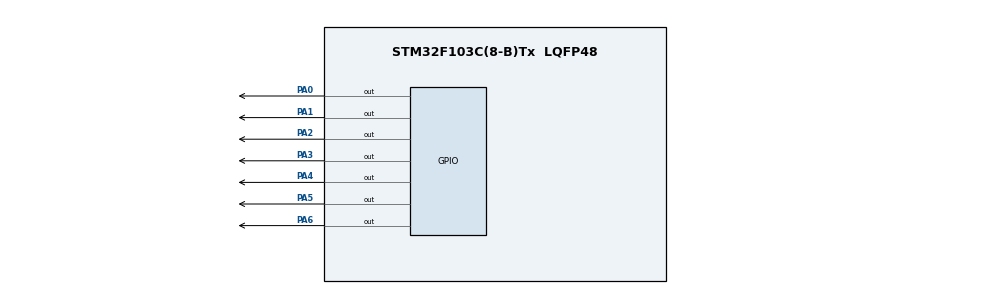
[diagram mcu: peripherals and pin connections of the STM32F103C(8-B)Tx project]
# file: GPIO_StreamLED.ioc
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Mcu.Family=STM32F1
Mcu.Name=STM32F103C(8-B)Tx
Mcu.Package=LQFP48
NVIC.PriorityGroup=NVIC_PRIORITYGROUP_4
PA0-WKUP.Signal=GPIO_Output
PA1.Signal=GPIO_Output
PA13.Mode=Serial_Wire
PA13.Signal=SYS_JTMS-SWDIO
PA14.Mode=Serial_Wire
PA14.Signal=SYS_JTCK-SWCLK
PA2.Signal=GPIO_Output
PA3.Signal=GPIO_Output
PA4.Signal=GPIO_Output
PA5.Signal=GPIO_Output
PA6.Signal=GPIO_Output
PD0-OSC_IN.Mode=HSE-External-Oscillator
PD0-OSC_IN.Signal=RCC_OSC_IN
PD1-OSC_OUT.Mode=HSE-External-Oscillator
PD1-OSC_OUT.Signal=RCC_OSC_OUT
ProjectManager.HeapSize=0x200
ProjectManager.StackSize=0x400
ProjectManager.TargetToolchain=STM32CubeIDE
RCC.AHBFreq_Value=72000000
RCC.APB1CLKDivider=RCC_HCLK_DIV2
RCC.APB1Freq_Value=36000000
RCC.APB1TimFreq_Value=72000000
RCC.APB2Freq_Value=72000000
RCC.APB2TimFreq_Value=72000000
RCC.HCLKFreq_Value=72000000
RCC.PLLMUL=RCC_PLL_MUL9
RCC.PLLSourceVirtual=RCC_PLLSOURCE_HSE
RCC.SYSCLKFreq_VALUE=72000000
RCC.SYSCLKSource=RCC_SYSCLKSOURCE_PLLCLK
RCC.USBFreq_Value=72000000
board=custom

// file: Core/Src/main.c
/* USER CODE BEGIN Header */
/**
  ******************************************************************************
  * @file           : main.c
  * @brief          : Main program body
  ******************************************************************************
  * @attention
  *
  * Copyright (c) 2026 STMicroelectronics.
  * All rights reserved.
  *
  * This software is licensed under terms that can be found in the LICENSE file
  * in the root directory of this software component.
  * If no LICENSE file comes with this software, it is provided AS-IS.
  *
  ******************************************************************************
  */
/* USER CODE END Header */
#include "main.h"

void SystemClock_Config(void);
static void MX_GPIO_Init(void);

int main(void)
{

  /* USER CODE BEGIN 1 */
	uint16_t led_pin[] = {GPIO_PIN_0, GPIO_PIN_1, GPIO_PIN_2, GPIO_PIN_3,
	                      GPIO_PIN_4, GPIO_PIN_5, GPIO_PIN_6};
	uint8_t led_count = sizeof(led_pin) / sizeof(led_pin[0]);
	int8_t led_index = 0;
	uint32_t delay_time = 500; // 每步 500 ms
	int8_t direction = 1; // 1 for forward, -1 for backward
  /* USER CODE END 1 */

  /* MCU Configuration--------------------------------------------------------*/

  /* Reset of all peripherals, Initializes the Flash interface and the Systick. */
  HAL_Init();

  /* Configure the system clock */
  SystemClock_Config();

  /* Initialize all configured peripherals */
  MX_GPIO_Init();

  /* Infinite loop */
  while (1)
  {

    /* USER CODE BEGIN 3 */
	  for (uint8_t i = 0; i < led_count; i++) {
		  HAL_GPIO_WritePin(GPIOA, led_pin[i], GPIO_PIN_RESET);
	  }
	  HAL_GPIO_WritePin(GPIOA, led_pin[led_index], GPIO_PIN_SET);

	  HAL_Delay(delay_time);

	  if (led_index >= led_count - 1) {
		  direction = -1;
	  } else if (led_index <= 0) {
		  direction = 1;
	  }
	  led_index += direction;
  }
  /* USER CODE END 3 */
}

void SystemClock_Config(void)
{
  RCC_OscInitTypeDef RCC_OscInitStruct = {0};
  RCC_ClkInitTypeDef RCC_ClkInitStruct = {0};
  uint32_t sysclk_source = RCC_SYSCLKSOURCE_PLLCLK;

  /** Initializes the RCC Oscillators according to the specified parameters
  * in the RCC_OscInitTypeDef structure.
  */
  RCC_OscInitStruct.OscillatorType = RCC_OSCILLATORTYPE_HSE;
  RCC_OscInitStruct.HSEState = RCC_HSE_ON;
  RCC_OscInitStruct.HSEPredivValue = RCC_HSE_PREDIV_DIV1;
  RCC_OscInitStruct.HSIState = RCC_HSI_ON;
  RCC_OscInitStruct.PLL.PLLState = RCC_PLL_ON;
  RCC_OscInitStruct.PLL.PLLSource = RCC_PLLSOURCE_HSE;
  RCC_OscInitStruct.PLL.PLLMUL = RCC_PLL_MUL9;
  if (HAL_RCC_OscConfig(&RCC_OscInitStruct) != HAL_OK)
  {
    /* HSE 起振失败：退回内部 HSI(8MHz)，保证 GPIO 仍能正常初始化 */
    RCC_OscInitStruct.OscillatorType = RCC_OSCILLATORTYPE_HSI;
    RCC_OscInitStruct.HSEState = RCC_HSE_OFF;
    RCC_OscInitStruct.HSIState = RCC_HSI_ON;
    RCC_OscInitStruct.HSICalibrationValue = RCC_HSICALIBRATION_DEFAULT;
    RCC_OscInitStruct.PLL.PLLState = RCC_PLL_OFF;
    if (HAL_RCC_OscConfig(&RCC_OscInitStruct) != HAL_OK)
    {
      Error_Handler();
    }
    sysclk_source = RCC_SYSCLKSOURCE_HSI;
  }

  /** Initializes the CPU, AHB and APB buses clocks
  */
  RCC_ClkInitStruct.ClockType = RCC_CLOCKTYPE_HCLK|RCC_CLOCKTYPE_SYSCLK
                              |RCC_CLOCKTYPE_PCLK1|RCC_CLOCKTYPE_PCLK2;
  RCC_ClkInitStruct.SYSCLKSource = sysclk_source;
  RCC_ClkInitStruct.AHBCLKDivider = RCC_SYSCLK_DIV1;
  RCC_ClkInitStruct.APB1CLKDivider = RCC_HCLK_DIV2;
  RCC_ClkInitStruct.APB2CLKDivider = RCC_HCLK_DIV1;

  if (HAL_RCC_ClockConfig(&RCC_ClkInitStruct, FLASH_LATENCY_2) != HAL_OK)
  {
    Error_Handler();
  }
}

static void MX_GPIO_Init(void)
{
  GPIO_InitTypeDef GPIO_InitStruct = {0};

  /* GPIO Ports Clock Enable */
  __HAL_RCC_GPIOD_CLK_ENABLE();
  __HAL_RCC_GPIOA_CLK_ENABLE();

  /*Configure GPIO pin Output Level */
  HAL_GPIO_WritePin(GPIOA, GPIO_PIN_0|GPIO_PIN_1|GPIO_PIN_2|GPIO_PIN_3
                          |GPIO_PIN_4|GPIO_PIN_5|GPIO_PIN_6, GPIO_PIN_RESET);

  /*Configure GPIO pins : PA0 PA1 PA2 PA3
                           PA4 PA5 PA6 */
  GPIO_InitStruct.Pin = GPIO_PIN_0|GPIO_PIN_1|GPIO_PIN_2|GPIO_PIN_3
                          |GPIO_PIN_4|GPIO_PIN_5|GPIO_PIN_6;
  GPIO_InitStruct.Mode = GPIO_MODE_OUTPUT_PP;
  GPIO_InitStruct.Pull = GPIO_NOPULL;
  GPIO_InitStruct.Speed = GPIO_SPEED_FREQ_LOW;
  HAL_GPIO_Init(GPIOA, &GPIO_InitStruct);

}

void Error_Handler(void)
{
  __disable_irq();
  while (1)
  {
  }
}
